VERSION 5.7 ;
BUSBITCHARS "[]" ;
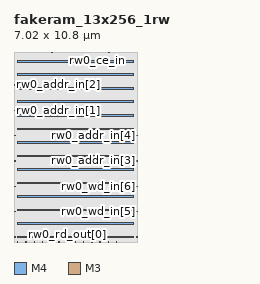
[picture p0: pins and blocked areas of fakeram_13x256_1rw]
MACRO fakeram_13x256_1rw
  FOREIGN fakeram_13x256_1rw 0 0 ;
  SYMMETRY X Y R90 ;
  SIZE 7.020 BY 10.800 ;
  CLASS BLOCK ;
  PIN rw0_wd_in[0]
    DIRECTION INPUT ;
    USE SIGNAL ;
    SHAPE ABUTMENT ;
    PORT
      LAYER M4 ;
      RECT 0.000 0.276 0.072 0.300 ;
    END
  END rw0_wd_in[0]
  PIN rw0_wd_in[1]
    DIRECTION INPUT ;
    USE SIGNAL ;
    SHAPE ABUTMENT ;
    PORT
      LAYER M4 ;
      RECT 0.000 1.716 0.072 1.740 ;
    END
  END rw0_wd_in[1]
  PIN rw0_wd_in[2]
    DIRECTION INPUT ;
    USE SIGNAL ;
    SHAPE ABUTMENT ;
    PORT
      LAYER M4 ;
      RECT 0.000 3.156 0.072 3.180 ;
    END
  END rw0_wd_in[2]
  PIN rw0_wd_in[3]
    DIRECTION INPUT ;
    USE SIGNAL ;
    SHAPE ABUTMENT ;
    PORT
      LAYER M4 ;
      RECT 0.000 4.596 0.072 4.620 ;
    END
  END rw0_wd_in[3]
  PIN rw0_wd_in[4]
    DIRECTION INPUT ;
    USE SIGNAL ;
    SHAPE ABUTMENT ;
    PORT
      LAYER M4 ;
      RECT 6.948 0.276 7.020 0.300 ;
    END
  END rw0_wd_in[4]
  PIN rw0_wd_in[5]
    DIRECTION INPUT ;
    USE SIGNAL ;
    SHAPE ABUTMENT ;
    PORT
      LAYER M4 ;
      RECT 6.948 1.716 7.020 1.740 ;
    END
  END rw0_wd_in[5]
  PIN rw0_wd_in[6]
    DIRECTION INPUT ;
    USE SIGNAL ;
    SHAPE ABUTMENT ;
    PORT
      LAYER M4 ;
      RECT 6.948 3.156 7.020 3.180 ;
    END
  END rw0_wd_in[6]
  PIN rw0_wd_in[7]
    DIRECTION INPUT ;
    USE SIGNAL ;
    SHAPE ABUTMENT ;
    PORT
      LAYER M3 ;
      RECT 0.207 0.000 0.225 0.054 ;
    END
  END rw0_wd_in[7]
  PIN rw0_wd_in[8]
    DIRECTION INPUT ;
    USE SIGNAL ;
    SHAPE ABUTMENT ;
    PORT
      LAYER M3 ;
      RECT 0.675 0.000 0.693 0.054 ;
    END
  END rw0_wd_in[8]
  PIN rw0_wd_in[9]
    DIRECTION INPUT ;
    USE SIGNAL ;
    SHAPE ABUTMENT ;
    PORT
      LAYER M3 ;
      RECT 1.143 0.000 1.161 0.054 ;
    END
  END rw0_wd_in[9]
  PIN rw0_wd_in[10]
    DIRECTION INPUT ;
    USE SIGNAL ;
    SHAPE ABUTMENT ;
    PORT
      LAYER M3 ;
      RECT 1.611 0.000 1.629 0.054 ;
    END
  END rw0_wd_in[10]
  PIN rw0_wd_in[11]
    DIRECTION INPUT ;
    USE SIGNAL ;
    SHAPE ABUTMENT ;
    PORT
      LAYER M3 ;
      RECT 2.079 0.000 2.097 0.054 ;
    END
  END rw0_wd_in[11]
  PIN rw0_wd_in[12]
    DIRECTION INPUT ;
    USE SIGNAL ;
    SHAPE ABUTMENT ;
    PORT
      LAYER M3 ;
      RECT 2.547 0.000 2.565 0.054 ;
    END
  END rw0_wd_in[12]
  PIN rw0_rd_out[0]
    DIRECTION OUTPUT ;
    USE SIGNAL ;
    SHAPE ABUTMENT ;
    PORT
      LAYER M3 ;
      RECT 3.015 0.000 3.033 0.054 ;
    END
  END rw0_rd_out[0]
  PIN rw0_rd_out[1]
    DIRECTION OUTPUT ;
    USE SIGNAL ;
    SHAPE ABUTMENT ;
    PORT
      LAYER M3 ;
      RECT 3.483 0.000 3.501 0.054 ;
    END
  END rw0_rd_out[1]
  PIN rw0_rd_out[2]
    DIRECTION OUTPUT ;
    USE SIGNAL ;
    SHAPE ABUTMENT ;
    PORT
      LAYER M3 ;
      RECT 3.951 0.000 3.969 0.054 ;
    END
  END rw0_rd_out[2]
  PIN rw0_rd_out[3]
    DIRECTION OUTPUT ;
    USE SIGNAL ;
    SHAPE ABUTMENT ;
    PORT
      LAYER M3 ;
      RECT 4.419 0.000 4.437 0.054 ;
    END
  END rw0_rd_out[3]
  PIN rw0_rd_out[4]
    DIRECTION OUTPUT ;
    USE SIGNAL ;
    SHAPE ABUTMENT ;
    PORT
      LAYER M3 ;
      RECT 4.887 0.000 4.905 0.054 ;
    END
  END rw0_rd_out[4]
  PIN rw0_rd_out[5]
    DIRECTION OUTPUT ;
    USE SIGNAL ;
    SHAPE ABUTMENT ;
    PORT
      LAYER M3 ;
      RECT 5.355 0.000 5.373 0.054 ;
    END
  END rw0_rd_out[5]
  PIN rw0_rd_out[6]
    DIRECTION OUTPUT ;
    USE SIGNAL ;
    SHAPE ABUTMENT ;
    PORT
      LAYER M3 ;
      RECT 5.823 0.000 5.841 0.054 ;
    END
  END rw0_rd_out[6]
  PIN rw0_rd_out[7]
    DIRECTION OUTPUT ;
    USE SIGNAL ;
    SHAPE ABUTMENT ;
    PORT
      LAYER M3 ;
      RECT 0.207 10.746 0.225 10.800 ;
    END
  END rw0_rd_out[7]
  PIN rw0_rd_out[8]
    DIRECTION OUTPUT ;
    USE SIGNAL ;
    SHAPE ABUTMENT ;
    PORT
      LAYER M3 ;
      RECT 0.855 10.746 0.873 10.800 ;
    END
  END rw0_rd_out[8]
  PIN rw0_rd_out[9]
    DIRECTION OUTPUT ;
    USE SIGNAL ;
    SHAPE ABUTMENT ;
    PORT
      LAYER M3 ;
      RECT 1.503 10.746 1.521 10.800 ;
    END
  END rw0_rd_out[9]
  PIN rw0_rd_out[10]
    DIRECTION OUTPUT ;
    USE SIGNAL ;
    SHAPE ABUTMENT ;
    PORT
      LAYER M3 ;
      RECT 2.151 10.746 2.169 10.800 ;
    END
  END rw0_rd_out[10]
  PIN rw0_rd_out[11]
    DIRECTION OUTPUT ;
    USE SIGNAL ;
    SHAPE ABUTMENT ;
    PORT
      LAYER M3 ;
      RECT 2.799 10.746 2.817 10.800 ;
    END
  END rw0_rd_out[11]
  PIN rw0_rd_out[12]
    DIRECTION OUTPUT ;
    USE SIGNAL ;
    SHAPE ABUTMENT ;
    PORT
      LAYER M3 ;
      RECT 3.447 10.746 3.465 10.800 ;
    END
  END rw0_rd_out[12]
  PIN rw0_addr_in[0]
    DIRECTION INPUT ;
    USE SIGNAL ;
    SHAPE ABUTMENT ;
    PORT
      LAYER M4 ;
      RECT 0.000 6.036 0.072 6.060 ;
    END
  END rw0_addr_in[0]
  PIN rw0_addr_in[1]
    DIRECTION INPUT ;
    USE SIGNAL ;
    SHAPE ABUTMENT ;
    PORT
      LAYER M4 ;
      RECT 0.000 7.476 0.072 7.500 ;
    END
  END rw0_addr_in[1]
  PIN rw0_addr_in[2]
    DIRECTION INPUT ;
    USE SIGNAL ;
    SHAPE ABUTMENT ;
    PORT
      LAYER M4 ;
      RECT 0.000 8.916 0.072 8.940 ;
    END
  END rw0_addr_in[2]
  PIN rw0_addr_in[3]
    DIRECTION INPUT ;
    USE SIGNAL ;
    SHAPE ABUTMENT ;
    PORT
      LAYER M4 ;
      RECT 6.948 4.596 7.020 4.620 ;
    END
  END rw0_addr_in[3]
  PIN rw0_addr_in[4]
    DIRECTION INPUT ;
    USE SIGNAL ;
    SHAPE ABUTMENT ;
    PORT
      LAYER M4 ;
      RECT 6.948 6.036 7.020 6.060 ;
    END
  END rw0_addr_in[4]
  PIN rw0_we_in
    DIRECTION INPUT ;
    USE SIGNAL ;
    SHAPE ABUTMENT ;
    PORT
      LAYER M3 ;
      RECT 4.095 10.746 4.113 10.800 ;
    END
  END rw0_we_in
  PIN rw0_ce_in
    DIRECTION INPUT ;
    USE SIGNAL ;
    SHAPE ABUTMENT ;
    PORT
      LAYER M3 ;
      RECT 4.743 10.746 4.761 10.800 ;
    END
  END rw0_ce_in
  PIN rw0_clk
    DIRECTION INPUT ;
    USE SIGNAL ;
    SHAPE ABUTMENT ;
    PORT
      LAYER M3 ;
      RECT 5.391 10.746 5.409 10.800 ;
    END
  END rw0_clk
  PIN VSS
    DIRECTION INOUT ;
    USE GROUND ;
    PORT
      LAYER M4 ;
      RECT 0.216 0.240 6.804 0.336 ;
      RECT 0.216 1.008 6.804 1.104 ;
      RECT 0.216 1.776 6.804 1.872 ;
      RECT 0.216 2.544 6.804 2.640 ;
      RECT 0.216 3.312 6.804 3.408 ;
      RECT 0.216 4.080 6.804 4.176 ;
      RECT 0.216 4.848 6.804 4.944 ;
      RECT 0.216 5.616 6.804 5.712 ;
      RECT 0.216 6.384 6.804 6.480 ;
      RECT 0.216 7.152 6.804 7.248 ;
      RECT 0.216 7.920 6.804 8.016 ;
      RECT 0.216 8.688 6.804 8.784 ;
      RECT 0.216 9.456 6.804 9.552 ;
      RECT 0.216 10.224 6.804 10.320 ;
    END
  END VSS
  PIN VDD
    DIRECTION INOUT ;
    USE POWER ;
    PORT
      LAYER M4 ;
      RECT 0.216 0.240 6.804 0.336 ;
      RECT 0.216 1.008 6.804 1.104 ;
      RECT 0.216 1.776 6.804 1.872 ;
      RECT 0.216 2.544 6.804 2.640 ;
      RECT 0.216 3.312 6.804 3.408 ;
      RECT 0.216 4.080 6.804 4.176 ;
      RECT 0.216 4.848 6.804 4.944 ;
      RECT 0.216 5.616 6.804 5.712 ;
      RECT 0.216 6.384 6.804 6.480 ;
      RECT 0.216 7.152 6.804 7.248 ;
      RECT 0.216 7.920 6.804 8.016 ;
      RECT 0.216 8.688 6.804 8.784 ;
      RECT 0.216 9.456 6.804 9.552 ;
      RECT 0.216 10.224 6.804 10.320 ;
    END
  END VDD
  OBS
    LAYER M1 ;
    RECT 0 0 7.020 10.800 ;
    LAYER M2 ;
    RECT 0 0 7.020 10.800 ;
    LAYER M3 ;
    RECT 0 0 7.020 10.800 ;
    LAYER M4 ;
    RECT 0 0 7.020 10.800 ;
  END
END fakeram_13x256_1rw

END LIBRARY
